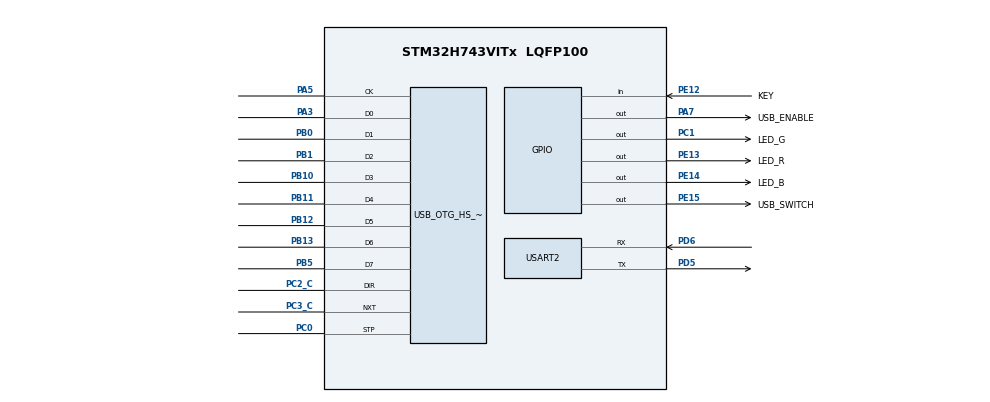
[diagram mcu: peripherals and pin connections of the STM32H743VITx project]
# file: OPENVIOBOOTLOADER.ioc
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CORTEX_M7.AccessPermission-Cortex_Memory_Protection_Unit_Region0_Settings=MPU_REGION_FULL_ACCESS
CORTEX_M7.BaseAddress-Cortex_Memory_Protection_Unit_Region0_Settings=0x24000000
CORTEX_M7.CPU_DCache=Disabled
CORTEX_M7.CPU_ICache=Disabled
CORTEX_M7.Enable-Cortex_Memory_Protection_Unit_Region0_Settings=MPU_REGION_ENABLE
CORTEX_M7.MPU_Control=__NULL
CORTEX_M7.Size-Cortex_Memory_Protection_Unit_Region0_Settings=MPU_REGION_SIZE_512KB
Dma.Request0=USART2_RX
Dma.Request1=USART2_TX
Dma.USART2_RX.0.Direction=DMA_PERIPH_TO_MEMORY
Dma.USART2_RX.0.EventEnable=DISABLE
Dma.USART2_RX.0.FIFOMode=DMA_FIFOMODE_DISABLE
Dma.USART2_RX.0.Instance=DMA1_Stream0
Dma.USART2_RX.0.MemDataAlignment=DMA_MDATAALIGN_BYTE
Dma.USART2_RX.0.MemInc=DMA_MINC_ENABLE
Dma.USART2_RX.0.Mode=DMA_NORMAL
Dma.USART2_RX.0.PeriphDataAlignment=DMA_PDATAALIGN_BYTE
Dma.USART2_RX.0.PeriphInc=DMA_PINC_DISABLE
Dma.USART2_RX.0.Polarity=HAL_DMAMUX_REQ_GEN_RISING
Dma.USART2_RX.0.Priority=DMA_PRIORITY_LOW
Dma.USART2_RX.0.RequestNumber=1
Dma.USART2_RX.0.SignalID=NONE
Dma.USART2_RX.0.SyncEnable=DISABLE
Dma.USART2_RX.0.SyncPolarity=HAL_DMAMUX_SYNC_NO_EVENT
Dma.USART2_RX.0.SyncRequestNumber=1
Dma.USART2_RX.0.SyncSignalID=NONE
Dma.USART2_TX.1.Direction=DMA_MEMORY_TO_PERIPH
Dma.USART2_TX.1.EventEnable=DISABLE
Dma.USART2_TX.1.FIFOMode=DMA_FIFOMODE_DISABLE
Dma.USART2_TX.1.Instance=DMA1_Stream1
Dma.USART2_TX.1.MemDataAlignment=DMA_MDATAALIGN_BYTE
Dma.USART2_TX.1.MemInc=DMA_MINC_ENABLE
Dma.USART2_TX.1.Mode=DMA_NORMAL
Dma.USART2_TX.1.PeriphDataAlignment=DMA_PDATAALIGN_BYTE
Dma.USART2_TX.1.PeriphInc=DMA_PINC_DISABLE
Dma.USART2_TX.1.Polarity=HAL_DMAMUX_REQ_GEN_RISING
Dma.USART2_TX.1.Priority=DMA_PRIORITY_LOW
Dma.USART2_TX.1.RequestNumber=1
Dma.USART2_TX.1.SignalID=NONE
Dma.USART2_TX.1.SyncEnable=DISABLE
Dma.USART2_TX.1.SyncPolarity=HAL_DMAMUX_SYNC_NO_EVENT
Dma.USART2_TX.1.SyncRequestNumber=1
Dma.USART2_TX.1.SyncSignalID=NONE
Mcu.Family=STM32H7
Mcu.Name=STM32H743VITx
Mcu.Package=LQFP100
NVIC.DMA1_Stream0_IRQn=true\:0\:0\:false\:false\:true\:false\:true
NVIC.DMA1_Stream1_IRQn=true\:0\:0\:false\:false\:true\:false\:true
NVIC.OTG_HS_EP1_IN_IRQn=true\:0\:0\:false\:false\:true\:true\:true
NVIC.OTG_HS_EP1_OUT_IRQn=true\:0\:0\:false\:false\:true\:true\:true
NVIC.OTG_HS_IRQn=true\:0\:0\:false\:false\:true\:true\:true
NVIC.PriorityGroup=NVIC_PRIORITYGROUP_4
PA13\ (JTMS/SWDIO).Mode=Serial_Wire
PA13\ (JTMS/SWDIO).Signal=DEBUG_JTMS-SWDIO
PA14\ (JTCK/SWCLK).Mode=Serial_Wire
PA14\ (JTCK/SWCLK).Signal=DEBUG_JTCK-SWCLK
PA3.Mode=Device_HS
PA3.Signal=USB_OTG_HS_ULPI_D0
PA5.Mode=Device_HS
PA5.Signal=USB_OTG_HS_ULPI_CK
PA7.GPIO_Label=USB_ENABLE
PA7.PinState=GPIO_PIN_SET
PA7.Signal=GPIO_Output
PB0.Mode=Device_HS
PB0.Signal=USB_OTG_HS_ULPI_D1
PB1.Mode=Device_HS
PB1.Signal=USB_OTG_HS_ULPI_D2
PB10.Mode=Device_HS
PB10.Signal=USB_OTG_HS_ULPI_D3
PB11.Mode=Device_HS
PB11.Signal=USB_OTG_HS_ULPI_D4
PB12.Mode=Device_HS
PB12.Signal=USB_OTG_HS_ULPI_D5
PB13.Mode=Device_HS
PB13.Signal=USB_OTG_HS_ULPI_D6
PB5.Mode=Device_HS
PB5.Signal=USB_OTG_HS_ULPI_D7
PC0.Mode=Device_HS
PC0.Signal=USB_OTG_HS_ULPI_STP
PC1.GPIO_Label=LED_G
PC1.PinState=GPIO_PIN_SET
PC1.Signal=GPIO_Output
PC2_C.Mode=Device_HS
PC2_C.Signal=USB_OTG_HS_ULPI_DIR
PC3_C.Mode=Device_HS
PC3_C.Signal=USB_OTG_HS_ULPI_NXT
PD5.Mode=Asynchronous
PD5.Signal=USART2_TX
PD6.Mode=Asynchronous
PD6.Signal=USART2_RX
PE12.GPIO_Label=KEY
PE12.GPIO_PuPd=GPIO_PULLUP
PE12.Signal=GPIO_Input
PE13.GPIO_Label=LED_R
PE13.PinState=GPIO_PIN_SET
PE13.Signal=GPIO_Output
PE14.GPIO_Label=LED_B
PE14.GPIO_Speed=GPIO_SPEED_FREQ_VERY_HIGH
PE14.PinState=GPIO_PIN_SET
PE14.Signal=GPIO_Output
PE15.GPIO_Label=USB_SWITCH
PE15.PinState=GPIO_PIN_RESET
PE15.Signal=GPIO_Output
PH0-OSC_IN\ (PH0).Mode=HSE-External-Oscillator
PH0-OSC_IN\ (PH0).Signal=RCC_OSC_IN
PH1-OSC_OUT\ (PH1).Mode=HSE-External-Oscillator
PH1-OSC_OUT\ (PH1).Signal=RCC_OSC_OUT
ProjectManager.HeapSize=0xA00
ProjectManager.StackSize=0x1000
ProjectManager.TargetToolchain=Makefile
RCC.ADCCLockSelection=RCC_ADCCLKSOURCE_CLKP
RCC.ADCFreq_Value=64000000
RCC.APB1Freq_Value=100000000
RCC.APB2Freq_Value=100000000
RCC.APB3Freq_Value=100000000
RCC.APB4Freq_Value=100000000
RCC.CortexFreq_Value=400000000
RCC.D1PPRE=RCC_APB3_DIV2
RCC.D2PPRE1=RCC_APB1_DIV2
RCC.D2PPRE2=RCC_APB2_DIV2
RCC.D3PPRE=RCC_APB4_DIV2
RCC.DIVM1=3
RCC.DIVM2=6
RCC.DIVM3=6
RCC.DIVN1=200
RCC.DIVN2=112
RCC.DIVN3=400
RCC.DIVP2=1
RCC.DIVQ1=20
RCC.DIVQ3=4
RCC.DIVR1=20
RCC.DIVR2=16
RCC.HCLKFreq_Value=200000000
RCC.HPRE=RCC_HCLK_DIV2
RCC.HSE_VALUE=12000000
RCC.PLL2FRACN=0
RCC.PLL3FRACN=0
RCC.PLLFRACN=0
RCC.PLLSourceVirtual=RCC_PLLSOURCE_HSE
RCC.RCC_MCO1Source=RCC_MCO1SOURCE_PLL1QCLK
RCC.RCC_MCODiv1=RCC_MCODIV_2
RCC.SPI123CLockSelection=RCC_SPI123CLKSOURCE_PLL2
RCC.SYSCLKFreq_VALUE=400000000
RCC.SYSCLKSource=RCC_SYSCLKSOURCE_PLLCLK
RCC.USBCLockSelection=RCC_USBCLKSOURCE_HSI48
RCC.USBFreq_Value=48000000
USART2.VirtualMode-Asynchronous=VM_ASYNC
USB_DEVICE.CLASS_NAME_HS=CDC
USB_DEVICE.VirtualMode-CDC_HS=Cdc
USB_DEVICE.VirtualModeHS=Cdc_HS
USB_OTG_HS.VirtualMode-Device_HS=Device_HS
USB_OTG_HS.dma_enable-Device_HS=DISABLE
VP_USB_DEVICE_VS_USB_DEVICE_CDC_HS.Mode=CDC_HS
board=custom

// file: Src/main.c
/* USER CODE BEGIN Header */
/**
  ******************************************************************************
  * @file           : main.c
  * @brief          : Main program body
  ******************************************************************************
  * @attention
  *
  * <h2><center>&copy; Copyright (c) 2019 STMicroelectronics.
  * All rights reserved.</center></h2>
  *
  * This software component is licensed by ST under Ultimate Liberty license
  * SLA0044, the "License"; You may not use this file except in compliance with
  * the License. You may obtain a copy of the License at:
  *                             www.st.com/SLA0044
  *
  ******************************************************************************
  */
/* USER CODE END Header */
#include "main.h"
#include "dma.h"
#include "usart.h"
#include "usb_device.h"
#include "gpio.h"

/* USER CODE BEGIN Includes */
#include "iap.h"
/* USER CODE END Includes */

void SystemClock_Config(void);
/* USER CODE BEGIN PFP */
uint32_t timer_cnt = 0;
/* USER CODE END PFP */

int main(void)
{

  /* MCU Configuration--------------------------------------------------------*/

  /* Reset of all peripherals, Initializes the Flash interface and the Systick. */
  HAL_Init();

  /* Configure the system clock */
  SystemClock_Config();

  /* Initialize all configured peripherals */
  MX_GPIO_Init();
  MX_DMA_Init();
  MX_USB_DEVICE_Init();
  MX_USART2_UART_Init();
  /* USER CODE BEGIN 2 */

  printf("[ openvio bootloader ]\r\n");

  boot();
  /* USER CODE END 2 */

  /* Infinite loop */
  while (1)
  {

    /* USER CODE BEGIN 3 */
    //CDC_Transmit_HS("hello",sizeof("hello"));
  }
  /* USER CODE END 3 */
}

void SystemClock_Config(void)
{
  RCC_OscInitTypeDef RCC_OscInitStruct = {0};
  RCC_ClkInitTypeDef RCC_ClkInitStruct = {0};

  /** Supply configuration update enable
  */
  HAL_PWREx_ConfigSupply(PWR_LDO_SUPPLY);
  /** Configure the main internal regulator output voltage
  */
  __HAL_PWR_VOLTAGESCALING_CONFIG(PWR_REGULATOR_VOLTAGE_SCALE0);

  while(!__HAL_PWR_GET_FLAG(PWR_FLAG_VOSRDY)) {}
  /** Initializes the RCC Oscillators according to the specified parameters
  * in the RCC_OscInitTypeDef structure.
  */
  RCC_OscInitStruct.OscillatorType = RCC_OSCILLATORTYPE_HSI48|RCC_OSCILLATORTYPE_HSE;
  RCC_OscInitStruct.HSEState = RCC_HSE_ON;
  RCC_OscInitStruct.HSI48State = RCC_HSI48_ON;
  RCC_OscInitStruct.PLL.PLLState = RCC_PLL_ON;
  RCC_OscInitStruct.PLL.PLLSource = RCC_PLLSOURCE_HSE;
  RCC_OscInitStruct.PLL.PLLM = 1;
  RCC_OscInitStruct.PLL.PLLN = 80;
  RCC_OscInitStruct.PLL.PLLP = 2;
  RCC_OscInitStruct.PLL.PLLQ = 10;
  RCC_OscInitStruct.PLL.PLLR = 2;
  RCC_OscInitStruct.PLL.PLLRGE = RCC_PLL1VCIRANGE_3;
  RCC_OscInitStruct.PLL.PLLVCOSEL = RCC_PLL1VCOWIDE;
  RCC_OscInitStruct.PLL.PLLFRACN = 0;
  if (HAL_RCC_OscConfig(&RCC_OscInitStruct) != HAL_OK)
  {
    Error_Handler();
  }
  /** Initializes the CPU, AHB and APB buses clocks
  */
  RCC_ClkInitStruct.ClockType = RCC_CLOCKTYPE_HCLK|RCC_CLOCKTYPE_SYSCLK
                              |RCC_CLOCKTYPE_PCLK1|RCC_CLOCKTYPE_PCLK2
                              |RCC_CLOCKTYPE_D3PCLK1|RCC_CLOCKTYPE_D1PCLK1;
  RCC_ClkInitStruct.SYSCLKSource = RCC_SYSCLKSOURCE_PLLCLK;
  RCC_ClkInitStruct.SYSCLKDivider = RCC_SYSCLK_DIV1;
  RCC_ClkInitStruct.AHBCLKDivider = RCC_HCLK_DIV2;
  RCC_ClkInitStruct.APB3CLKDivider = RCC_APB3_DIV2;
  RCC_ClkInitStruct.APB1CLKDivider = RCC_APB1_DIV2;
  RCC_ClkInitStruct.APB2CLKDivider = RCC_APB2_DIV2;
  RCC_ClkInitStruct.APB4CLKDivider = RCC_APB4_DIV2;

  if (HAL_RCC_ClockConfig(&RCC_ClkInitStruct, FLASH_LATENCY_4) != HAL_OK)
  {
    Error_Handler();
  }
  HAL_RCC_MCOConfig(RCC_MCO1, RCC_MCO1SOURCE_PLL1QCLK, RCC_MCODIV_8);
}

void Error_Handler(void)
{
}

/************************ (C) COPYRIGHT STMicroelectronics *****END OF FILE****/
